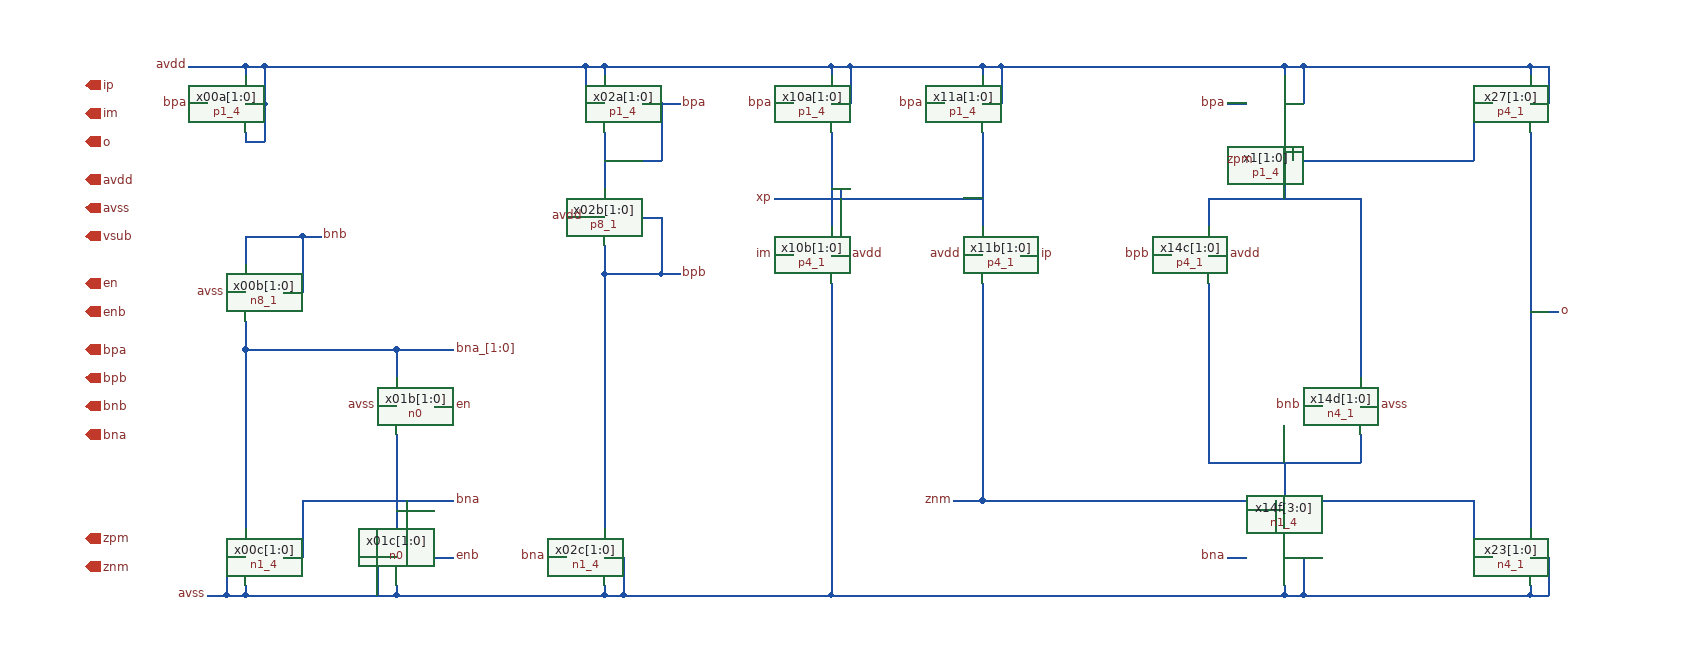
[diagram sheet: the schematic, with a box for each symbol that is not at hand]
v {xschem version=3.4.4 file_version=1.2
}
G {}
K {}
V {}
S {}
E {}
N 200 -160 220 -160 { lab=avss}
N 200 -160 200 -120 { lab=avss}
N 200 -120 220 -120 { lab=avss}
N 220 -130 220 -120 { lab=avss}
N 220 -500 220 -470 { lab=bnb}
N 220 -500 280 -500 { lab=bnb}
N 280 -500 280 -440 { lab=bnb}
N 260 -440 280 -440 { lab=bnb}
N 600 -130 600 -120 { lab=avss}
N 600 -460 660 -460 { lab=bpb}
N 660 -520 660 -460 { lab=bpb}
N 640 -520 660 -520 { lab=bpb}
N 600 -490 600 -460 { lab=bpb}
N 640 -640 660 -640 { lab=bpa}
N 580 -640 600 -640 { lab=avdd}
N 580 -680 580 -640 { lab=avdd}
N 600 -160 620 -160 { lab=avss}
N 620 -160 620 -120 { lab=avss}
N 600 -120 620 -120 { lab=avss}
N 280 -500 300 -500 { lab=bnb}
N 660 -460 680 -460 { lab=bpb}
N 180 -120 200 -120 { lab=avss}
N 1000 -640 1020 -640 { lab=avdd}
N 1020 -680 1020 -640 { lab=avdd}
N 1000 -680 1020 -680 { lab=avdd}
N 1000 -680 1000 -670 { lab=avdd}
N 1320 -160 1340 -160 { lab=avss}
N 1340 -160 1340 -120 { lab=avss}
N 1320 -120 1340 -120 { lab=avss}
N 1320 -130 1320 -120 { lab=avss}
N 1260 -160 1280 -160 { lab=bna}
N 840 -640 860 -640 { lab=avdd}
N 860 -680 860 -640 { lab=avdd}
N 840 -680 860 -680 { lab=avdd}
N 840 -680 840 -670 { lab=avdd}
N 860 -680 1000 -680 { lab=avdd}
N 780 -640 800 -640 { lab=bpa}
N 940 -640 960 -640 { lab=bpa}
N 780 -540 1000 -540 { lab=xp}
N 850 -550 850 -540 { lab=xp}
N 980 -480 1000 -480 { lab=avdd}
N 840 -480 860 -480 { lab=avdd}
N 1180 -480 1200 -480 { lab=bpb}
N 1340 -320 1360 -320 { lab=bnb}
N 1240 -480 1260 -480 { lab=avdd}
N 1400 -320 1420 -320 { lab=avss}
N 1240 -260 1400 -260 { lab=znm}
N 1240 -450 1240 -260 { lab=znm}
N 1400 -290 1400 -260 { lab=znm}
N 1240 -540 1240 -510 { lab=zpm}
N 1240 -540 1400 -540 { lab=zpm}
N 1400 -540 1400 -350 { lab=zpm}
N 1040 -480 1060 -480 { lab=ip}
N 780 -480 800 -480 { lab=im}
N 260 -160 280 -160 { lab=bna}
N 220 -120 380 -120 { lab=avss}
N 280 -220 280 -160 { lab=bna}
N 280 -220 440 -220 { lab=bna}
N 380 -130 380 -120 { lab=avss}
N 420 -160 440 -160 { lab=enb}
N 420 -320 440 -320 { lab=en}
N 380 -380 380 -350 { lab=bna_[1:0]}
N 360 -160 380 -160 { lab=avss}
N 360 -160 360 -120 { lab=avss}
N 390 -220 390 -210 { lab=bna}
N 380 -210 390 -210 { lab=bna}
N 220 -410 220 -380 { lab=bna_[1:0]}
N 220 -380 380 -380 { lab=bna_[1:0]}
N 380 -380 440 -380 { lab=bna_[1:0]}
N 660 -640 660 -580 { lab=bpa}
N 540 -160 560 -160 { lab=bna}
N 220 -640 240 -640 { lab=avdd}
N 240 -680 240 -640 { lab=avdd}
N 220 -680 240 -680 { lab=avdd}
N 220 -680 220 -670 { lab=avdd}
N 160 -640 180 -640 { lab=bpa}
N 240 -640 240 -600 { lab=avdd}
N 220 -600 240 -600 { lab=avdd}
N 220 -610 220 -600 { lab=avdd}
N 160 -680 220 -680 { lab=avdd}
N 1260 -640 1280 -640 { lab=bpa}
N 1320 -640 1340 -640 { lab=avdd}
N 1340 -680 1340 -640 { lab=avdd}
N 1320 -680 1340 -680 { lab=avdd}
N 1320 -680 1320 -670 { lab=avdd}
N 1580 -160 1600 -160 { lab=avss}
N 1600 -160 1600 -120 { lab=avss}
N 1580 -120 1600 -120 { lab=avss}
N 1580 -130 1580 -120 { lab=avss}
N 1520 -160 1540 -160 { lab=znm}
N 1520 -640 1540 -640 { lab=zpm}
N 1580 -640 1600 -640 { lab=avdd}
N 1600 -680 1600 -640 { lab=avdd}
N 1580 -680 1600 -680 { lab=avdd}
N 1580 -680 1580 -670 { lab=avdd}
N 1520 -220 1520 -160 {
lab=znm}
N 1520 -640 1520 -580 {
lab=zpm}
N 970 -220 1000 -220 {
lab=znm}
N 1580 -420 1610 -420 {
lab=o}
N 1340 -680 1580 -680 {
lab=avdd}
N 1340 -120 1580 -120 {
lab=avss}
N 380 -120 600 -120 {
lab=avss}
N 840 -450 840 -120 {
lab=avss}
N 1000 -220 1520 -220 {
lab=znm}
N 1000 -450 1000 -220 {
lab=znm}
N 840 -120 1320 -120 {
lab=avss}
N 1310 -220 1310 -210 {
lab=znm}
N 1310 -210 1320 -210 {
lab=znm}
N 1290 -580 1520 -580 {
lab=zpm}
N 1330 -590 1330 -580 {
lab=zpm}
N 1320 -590 1330 -590 {
lab=zpm}
N 1320 -260 1320 -190 {
lab=znm}
N 600 -580 660 -580 {
lab=bpa}
N 660 -640 680 -640 { lab=bpa}
N 1320 -610 1320 -540 {
lab=zpm}
N 840 -610 840 -510 {
lab=xp}
N 1000 -610 1000 -510 {
lab=xp}
N 840 -550 850 -550 {
lab=xp}
N 1020 -680 1320 -680 {
lab=avdd}
N 200 -440 220 -440 { lab=avss}
N 220 -380 220 -190 {
lab=bna_[1:0]}
N 580 -520 600 -520 { lab=avdd}
N 620 -120 840 -120 {
lab=avss}
N 600 -680 840 -680 {
lab=avdd}
N 600 -680 600 -670 {
lab=avdd}
N 240 -680 580 -680 {
lab=avdd}
N 580 -680 600 -680 {
lab=avdd}
N 1580 -610 1580 -190 {
lab=o}
N 380 -290 380 -190 {
lab=bna}
N 360 -320 380 -320 { lab=avss}
N 600 -610 600 -550 {
lab=bpa}
N 600 -460 600 -190 {
lab=bpb}
C {devices/title.sym} 160 -40 0 0 {name=l6 author="Luis Henrique Rodovalho"}
C {devices/iopin.sym} 50 -560 2 1 {name=pavdd lab=avdd}
C {devices/iopin.sym} 50 -530 2 1 {name=pavss lab=avss}
C {devices/iopin.sym} 50 -660 2 1 {name=pip lab=ip}
C {devices/iopin.sym} 50 -630 2 1 {name=pim lab=im}
C {devices/iopin.sym} 50 -600 2 1 {name=po lab=o}
C {n8_1.sym} 240 -440 0 1 {name=x00b[1:0]}
C {n1_4.sym} 580 -160 0 0 {name=x02c[1:0]}
C {p8_1.sym} 620 -520 0 1 {name=x02b[1:0]}
C {p1_4.sym} 620 -640 0 1 {name=x02a[1:0]}
C {devices/lab_pin.sym} 300 -500 2 0 {name=l10 sig_type=std_logic lab=bnb}
C {devices/lab_pin.sym} 440 -220 2 0 {name=l11 sig_type=std_logic lab=bna}
C {devices/lab_pin.sym} 680 -460 2 0 {name=l12 sig_type=std_logic lab=bpb}
C {devices/lab_pin.sym} 180 -120 2 1 {name=lavss0 sig_type=std_logic lab=avss}
C {p4_1.sym} 820 -480 0 0 {name=x10b[1:0]}
C {p1_4.sym} 980 -640 0 0 {name=x11a[1:0]}
C {p4_1.sym} 1020 -480 0 1 {name=x11b[1:0]}
C {n1_4.sym} 1300 -160 0 0 {name=x14f[3:0]}
C {p1_4.sym} 820 -640 0 0 {name=x10a[1:0]}
C {devices/lab_pin.sym} 780 -640 2 1 {name=l19 sig_type=std_logic lab=bpa}
C {devices/lab_pin.sym} 940 -640 2 1 {name=l20 sig_type=std_logic lab=bpa}
C {devices/lab_pin.sym} 780 -540 2 1 {name=lxp sig_type=std_logic lab=xp}
C {devices/lab_pin.sym} 980 -480 2 1 {name=lavdd3 sig_type=std_logic lab=avdd}
C {devices/lab_pin.sym} 860 -480 2 0 {name=lavdd2 sig_type=std_logic lab=avdd}
C {p4_1.sym} 1220 -480 0 0 {name=x14c[1:0]}
C {devices/lab_pin.sym} 1180 -480 2 1 {name=l31 sig_type=std_logic lab=bpb}
C {n4_1.sym} 1380 -320 0 0 {name=x14d[1:0]}
C {devices/lab_pin.sym} 1340 -320 2 1 {name=l32 sig_type=std_logic lab=bnb}
C {devices/lab_pin.sym} 1260 -480 2 0 {name=lavdd4 sig_type=std_logic lab=avdd}
C {devices/lab_pin.sym} 1420 -320 2 0 {name=lavss4 sig_type=std_logic lab=avss}
C {devices/lab_pin.sym} 160 -680 2 1 {name=lavdd0 sig_type=std_logic lab=avdd}
C {devices/lab_pin.sym} 1060 -480 2 0 {name=l4 sig_type=std_logic lab=ip}
C {devices/lab_pin.sym} 780 -480 2 1 {name=l5 sig_type=std_logic lab=im}
C {devices/lab_pin.sym} 970 -220 2 1 {name=lznp sig_type=std_logic lab=znm}
C {n0.sym} 400 -160 0 1 {name=x01c[1:0]}
C {n0.sym} 400 -320 0 1 {name=x01b[1:0]}
C {n1_4.sym} 240 -160 0 1 {name=x00c[1:0]}
C {devices/lab_pin.sym} 440 -160 2 0 {name=l46 sig_type=std_logic lab=enb}
C {devices/lab_pin.sym} 440 -320 2 0 {name=l47 sig_type=std_logic lab=en}
C {devices/lab_pin.sym} 440 -380 2 0 {name=l9 sig_type=std_logic lab=bna_[1:0]}
C {devices/lab_pin.sym} 540 -160 2 1 {name=l50 sig_type=std_logic lab=bna}
C {devices/iopin.sym} 50 -380 2 1 {name=pbpa lab=bpa}
C {devices/iopin.sym} 50 -350 2 1 {name=pbpb lab=bpb}
C {devices/iopin.sym} 50 -320 2 1 {name=pbnb lab=bnb}
C {devices/iopin.sym} 50 -180 2 1 {name=pzpm lab=zpm}
C {devices/iopin.sym} 50 -150 2 1 {name=pznm lab=znm}
C {p1_4.sym} 200 -640 0 0 {name=x00a[1:0]}
C {devices/lab_pin.sym} 160 -640 2 1 {name=l16 sig_type=std_logic lab=bpa}
C {devices/iopin.sym} 50 -500 2 1 {name=pvsub lab=vsub}
C {devices/iopin.sym} 50 -450 2 1 {name=pen lab=en}
C {devices/iopin.sym} 50 -420 2 1 {name=penb lab=enb}
C {p1_4.sym} 1300 -640 0 0 {name=x1[1:0]}
C {devices/lab_pin.sym} 1260 -640 2 1 {name=l2 sig_type=std_logic lab=bpa}
C {devices/lab_pin.sym} 1290 -580 2 1 {name=lznp1 sig_type=std_logic lab=zpm}
C {n4_1.sym} 1560 -160 0 0 {name=x23[1:0]}
C {p4_1.sym} 1560 -640 0 0 {name=x27[1:0]}
C {devices/lab_pin.sym} 1610 -420 2 0 {name=l35 sig_type=std_logic lab=o}
C {devices/lab_pin.sym} 1260 -160 2 1 {name=l1 sig_type=std_logic lab=bna}
C {devices/iopin.sym} 50 -290 2 1 {name=pbnb1 lab=bna}
C {devices/lab_pin.sym} 680 -640 2 0 {name=l3 sig_type=std_logic lab=bpa}
C {devices/lab_pin.sym} 200 -440 2 1 {name=lavss1 sig_type=std_logic lab=avss}
C {devices/lab_pin.sym} 580 -520 2 1 {name=lavdd1 sig_type=std_logic lab=avdd}
C {devices/lab_pin.sym} 360 -320 2 1 {name=lavss2 sig_type=std_logic lab=avss}
